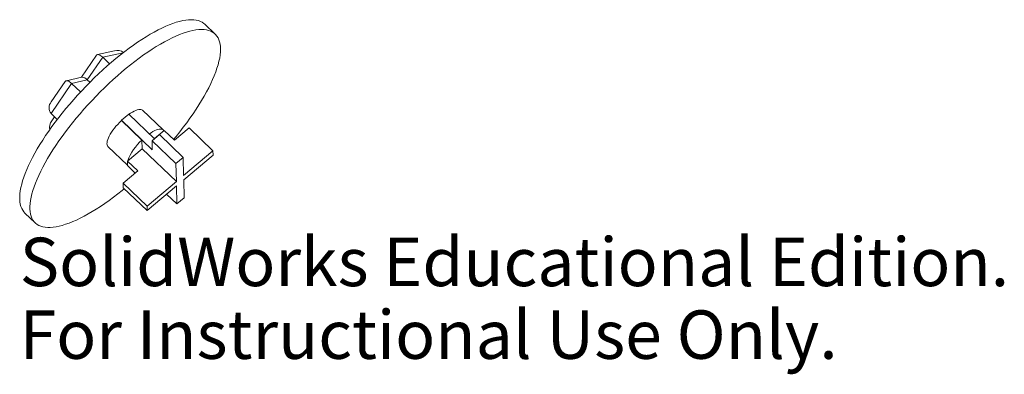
# Model space of a CAD drawing. Units: millimetres. Extents: x -9.5 to 88.6, y -25.5 to 9.9.
import ezdxf

# ---------------------------------------------------------------- set-up
doc = ezdxf.new("R2010")
doc.units = ezdxf.units.MM
doc.styles.add('SLDTEXTSTYLE0', font='TXT', dxfattribs={"width": 0.7})

msp = doc.modelspace()

# ---------------------------------------------------------------- linework, layer by layer
at = {"color": 7, "linetype": 'Continuous', "lineweight": 15}
for p, q in [((9.993, 8.434), (8.969, 9.41)), ((-1.853, 6.324), (-3.348, 4.125)), ((-1.226, 6.119), (-2.756, 3.869)), ((-0.061, 6.769), (-1.756, 6.389)), ((0.822, 6.579), (-1.226, 6.119)), ((-1.226, 6.119), (-0.536, 5.462)), ((-3.287, 4.139), (-4.856, 3.787)), ((-4.325, 3.517), (-6.367, 0.516)), ((-4.953, 3.721), (-6.347, 1.671)), ((-2.756, 3.869), (-4.325, 3.517)), ((-4.325, 3.517), (-3.431, 2.664)), ((-2.756, 3.869), (-2.502, 3.626)), ((-6.367, 0.516), (-5.749, -0.073)), ((-6.024, 0.19), (-6.309, -0.228)), ((1.367, 0.45), (0.636, -0.164)), ((3.931, -1.994), (1.367, 0.45)), ((4.797, -1.118), (2.749, 0.834)), ((0.636, -0.164), (0.636, -0.186)), ((3.708, -3.092), (0.636, -0.164)), ((0.636, -0.186), (2.685, -2.138)), ((7.38, -0.92), (5.918, -2.147)), ((7.38, -0.92), (9.769, -3.197)), ((4.421, -1.583), (3.69, -2.197)), ((4.894, -1.171), (3.923, -1.986)), ((6.81, -3.86), (4.421, -1.583)), ((5.918, -2.147), (4.894, -1.171)), ((-0.701, -2.786), (1.249, -4.644)), ((2.702, -3.011), (2.685, -2.138)), ((3.69, -2.197), (3.708, -3.092)), ((3.69, -2.197), (6.079, -4.474)), ((2.702, -3.011), (1.241, -4.238)), ((2.702, -3.011), (6.116, -6.264)), ((6.079, -4.474), (6.81, -3.86)), ((6.846, -5.651), (6.81, -3.86)), ((9.769, -3.197), (6.846, -5.651)), ((6.855, -6.098), (9.778, -3.644)), ((9.769, -3.197), (9.778, -3.644)), ((2.265, -5.214), (1.241, -4.238)), ((1.241, -4.238), (1.25, -4.685)), ((2.02, -5.419), (1.25, -4.685)), ((6.079, -4.474), (6.116, -6.264)), ((0.803, -6.441), (2.265, -5.214)), ((0.803, -6.441), (0.813, -6.888)), ((3.193, -8.718), (0.803, -6.441)), ((6.116, -6.264), (3.193, -8.718)), ((3.202, -9.166), (6.125, -6.712)), ((6.125, -6.712), (6.161, -8.502)), ((6.891, -7.889), (6.855, -6.098)), ((0.813, -6.888), (3.202, -9.166)), ((6.161, -8.502), (5.145, -7.534)), ((3.202, -9.166), (3.193, -8.718)), ((6.891, -7.889), (6.161, -8.502)), ((-8.969, -9.41), (-7.945, -10.386))]:
    msp.add_line(p, q, dxfattribs=at)
at = {"color": 7, "linetype": 'Continuous', "lineweight": 15, "flags": 128}
for points in [[(8.969, 9.41), (8.864, 9.501), (8.698, 9.614), (8.514, 9.707), (8.312, 9.779), (8.092, 9.831), (7.856, 9.862), (7.602, 9.872), (7.333, 9.861), (7.049, 9.83), (6.749, 9.778), (6.436, 9.706), (6.109, 9.613), (5.769, 9.5), (5.417, 9.367), (5.053, 9.214), (4.679, 9.042), (4.295, 8.85), (3.902, 8.641), (3.501, 8.413), (3.092, 8.167), (2.677, 7.904), (2.257, 7.625), (1.831, 7.329), (1.402, 7.018), (0.97, 6.693), (0.536, 6.353), (0.1, 6), (-0.335, 5.634), (-0.77, 5.256), (-1.204, 4.868), (-1.634, 4.469), (-2.062, 4.061), (-2.485, 3.644), (-2.902, 3.219), (-3.314, 2.788), (-3.719, 2.351), (-4.116, 1.909), (-4.504, 1.463), (-4.882, 1.014), (-5.251, 0.563), (-5.608, 0.11), (-5.954, -0.343), (-6.287, -0.795), (-6.607, -1.245), (-6.913, -1.692), (-7.204, -2.137), (-7.481, -2.576), (-7.741, -3.01), (-7.985, -3.438), (-8.213, -3.859), (-8.423, -4.271), (-8.616, -4.675), (-8.79, -5.069), (-8.946, -5.452), (-9.083, -5.823), (-9.201, -6.183), (-9.3, -6.529), (-9.379, -6.862), (-9.438, -7.18), (-9.478, -7.483), (-9.497, -7.77), (-9.497, -8.041), (-9.476, -8.295), (-9.436, -8.532), (-9.376, -8.751), (-9.296, -8.951), (-9.197, -9.132), (-9.078, -9.295), (-8.969, -9.41)], [(5.839, -2.071), (6.092, -1.764), (6.455, -1.312), (6.807, -0.86), (7.146, -0.407), (7.473, 0.044), (7.786, 0.493), (8.084, 0.939), (8.368, 1.381), (8.637, 1.818), (8.889, 2.249), (9.125, 2.674), (9.344, 3.09), (9.546, 3.498), (9.729, 3.897), (9.894, 4.286), (10.041, 4.663), (10.168, 5.029), (10.277, 5.381), (10.366, 5.721), (10.435, 6.047), (10.484, 6.357), (10.514, 6.653), (10.523, 6.932), (10.513, 7.194), (10.483, 7.44), (10.432, 7.668), (10.362, 7.877), (10.273, 8.068), (10.164, 8.24), (10.035, 8.392), (9.888, 8.525), (9.722, 8.638), (9.538, 8.731), (9.336, 8.803), (9.116, 8.855), (8.88, 8.886), (8.626, 8.896), (8.357, 8.885), (8.073, 8.854), (7.773, 8.802), (7.46, 8.73), (7.133, 8.637), (6.793, 8.524), (6.441, 8.391), (6.077, 8.238), (5.703, 8.066), (5.319, 7.874), (4.926, 7.665), (4.525, 7.437), (4.116, 7.191), (3.701, 6.928), (3.281, 6.649), (2.855, 6.353), (2.426, 6.042), (1.994, 5.717), (1.56, 5.377), (1.124, 5.024), (0.689, 4.658), (0.254, 4.28), (-0.18, 3.892), (-0.61, 3.493), (-1.038, 3.085), (-1.461, 2.668), (-1.878, 2.243), (-2.29, 1.812), (-2.695, 1.375), (-3.092, 0.933), (-3.48, 0.487), (-3.858, 0.038), (-4.227, -0.413), (-4.584, -0.866), (-4.93, -1.319), (-5.263, -1.771), (-5.583, -2.221), (-5.889, -2.668), (-6.18, -3.113), (-6.457, -3.552), (-6.717, -3.986), (-6.961, -4.414), (-7.189, -4.835), (-7.399, -5.247), (-7.592, -5.651), (-7.766, -6.045), (-7.922, -6.428), (-8.059, -6.799), (-8.177, -7.159), (-8.276, -7.505), (-8.355, -7.838), (-8.414, -8.156), (-8.454, -8.459), (-8.473, -8.746), (-8.473, -9.017), (-8.452, -9.271), (-8.412, -9.508), (-8.352, -9.727), (-8.272, -9.927), (-8.173, -10.108), (-8.054, -10.271), (-7.916, -10.413), (-7.759, -10.536), (-7.584, -10.639), (-7.391, -10.721), (-7.18, -10.783), (-6.952, -10.825), (-6.707, -10.845), (-6.446, -10.845), (-6.169, -10.824), (-5.877, -10.783), (-5.57, -10.72), (-5.25, -10.638), (-4.916, -10.535), (-4.57, -10.412), (-4.212, -10.269), (-3.843, -10.106), (-3.464, -9.924), (-3.076, -9.724), (-2.679, -9.505), (-2.274, -9.268), (-1.862, -9.014), (-1.444, -8.742), (-1.021, -8.455), (-0.593, -8.152), (-0.162, -7.833), (0.271, -7.5), (0.706, -7.154), (0.913, -6.984)], [(-1.226, 6.119), (-1.323, 6.205), (-1.417, 6.277), (-1.508, 6.332), (-1.593, 6.371), (-1.669, 6.391), (-1.737, 6.393), (-1.794, 6.376), (-1.839, 6.341), (-1.853, 6.324)], [(-4.953, 3.721), (-4.939, 3.738), (-4.894, 3.773), (-4.837, 3.79), (-4.769, 3.788), (-4.693, 3.768), (-4.608, 3.73), (-4.517, 3.674), (-4.423, 3.603), (-4.325, 3.517)], [(2.749, 0.834), (2.682, 0.881), (2.592, 0.912), (2.484, 0.922), (2.361, 0.912), (2.223, 0.88), (2.071, 0.827), (1.908, 0.755), (1.735, 0.663), (1.554, 0.554), (1.38, 0.437)], [(0.636, -0.186), (0.451, -0.372), (0.272, -0.565), (0.101, -0.762), (-0.06, -0.962), (-0.208, -1.161), (-0.343, -1.359), (-0.463, -1.552), (-0.566, -1.739), (-0.652, -1.918), (-0.719, -2.086), (-0.767, -2.242), (-0.795, -2.383), (-0.803, -2.51), (-0.79, -2.619), (-0.758, -2.71), (-0.705, -2.781), (-0.701, -2.786)], [(4.857, -1.202), (4.806, -1.128), (4.735, -1.074), (4.646, -1.041), (4.539, -1.03), (4.415, -1.039), (4.276, -1.071), (4.124, -1.123), (3.96, -1.195), (3.786, -1.287), (3.603, -1.397), (3.428, -1.515)]]:
    msp.add_lwpolyline(points, dxfattribs=at)
at = {"color": 7, "linetype": 'Continuous', "lineweight": 15}
for centre, radius, start, end in [((0.223, 5.745), 1.064, 53.71843, 105.47882), ((-3.282, 3.493), 0.646, 35.58474, 90.46511), ((-5.677, 1.082), 0.892, 138.71109, 219.36348), ((-5.501, -0.865), 1.028, 141.76163, 193.01696), ((5.949, -5.872), 4.96, 131.17259, 160.38726)]:
    msp.add_arc(centre, radius, start, end, dxfattribs=at)

# ---------------------------------------------------------------- texts
at = {"color": 7, "linetype": 'Continuous', "char_height": 4.83362, "attachment_point": 1, "style": 'SLDTEXTSTYLE0'}
for s, insert in [('SolidWorks Educational Edition.', (-9.497, -11.865)), ('For Instructional Use Only.', (-9.497, -19.115))]:
    msp.add_mtext(s, dxfattribs=dict(at, insert=insert))

doc.saveas('drawing.dxf')
